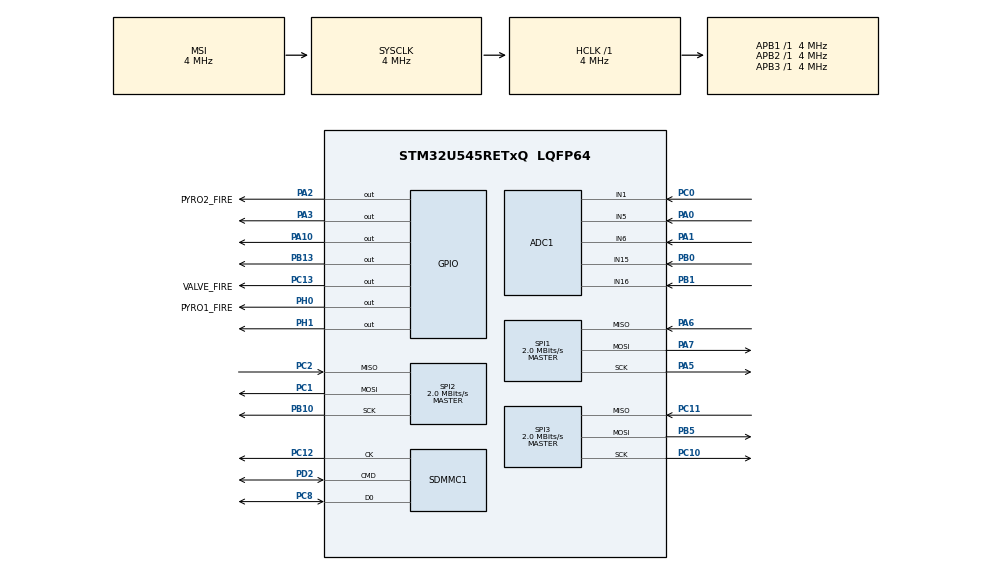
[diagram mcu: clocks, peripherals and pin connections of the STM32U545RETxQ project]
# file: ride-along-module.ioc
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ADC1.Channel-0\#ChannelRegularConversion=ADC_CHANNEL_15
ADC1.MonitoredBy-0\#ChannelRegularConversion=__NULL
ADC1.NbrOfConversionFlag=1
ADC1.OffsetNumber-0\#ChannelRegularConversion=ADC_OFFSET_NONE
ADC1.Rank-0\#ChannelRegularConversion=1
ADC1.SamplingTime-0\#ChannelRegularConversion=ADC_SAMPLETIME_5CYCLE
ADC1.master=1
CORTEX_M33_NS.userName=CORTEX_M33
Mcu.Family=STM32U5
Mcu.Name=STM32U545RETxQ
Mcu.Package=LQFP64
NVIC.PriorityGroup=NVIC_PRIORITYGROUP_4
NVIC.TIM16_IRQn=true\:0\:0\:false\:false\:true\:true\:true\:true
PA0.Mode=IN5-Single-Ended
PA0.Signal=ADC1_IN5
PA1.Mode=IN6-Single-Ended
PA1.Signal=ADC1_IN6
PA10.Signal=GPIO_Output
PA2.GPIO_Label=PYRO2_FIRE
PA2.Signal=GPIO_Output
PA3.Signal=GPIO_Output
PA5.Mode=Full_Duplex_Master
PA5.Signal=SPI1_SCK
PA6.Mode=Full_Duplex_Master
PA6.Signal=SPI1_MISO
PA7.Mode=Full_Duplex_Master
PA7.Signal=SPI1_MOSI
PB0.Mode=IN15-Single-Ended
PB0.Signal=ADC1_IN15
PB1.Mode=IN16-Single-Ended
PB1.Signal=ADC1_IN16
PB10.Mode=Full_Duplex_Master
PB10.Signal=SPI2_SCK
PB13.Signal=GPIO_Output
PB5.Mode=Full_Duplex_Master
PB5.Signal=SPI3_MOSI
PC0.Mode=IN1-Single-Ended
PC0.Signal=ADC1_IN1
PC1.Mode=Full_Duplex_Master
PC1.Signal=SPI2_MOSI
PC10.Mode=Full_Duplex_Master
PC10.Signal=SPI3_SCK
PC11.Mode=Full_Duplex_Master
PC11.Signal=SPI3_MISO
PC12.Mode=SD_1_bit
PC12.Signal=SDMMC1_CK
PC13.GPIO_Label=VALVE_FIRE
PC13.Signal=GPIO_Output
PC2.Mode=Full_Duplex_Master
PC2.Signal=SPI2_MISO
PC8.GPIO_PuPd=GPIO_PULLUP
PC8.Mode=SD_1_bit
PC8.Signal=SDMMC1_D0
PD2.GPIO_PuPd=GPIO_PULLUP
PD2.Mode=SD_1_bit
PD2.Signal=SDMMC1_CMD
PH0-OSC_IN\ (PH0).GPIO_Label=PYRO1_FIRE
PH0-OSC_IN\ (PH0).Signal=GPIO_Output
PH1-OSC_OUT\ (PH1).Signal=GPIO_Output
ProjectManager.HeapSize=0x200
ProjectManager.StackSize=0x400
ProjectManager.TargetToolchain=STM32CubeIDE
RCC.ADCFreq_Value=16000000
RCC.AHBFreq_Value=4000000
RCC.APB1Freq_Value=4000000
RCC.APB1TimFreq_Value=4000000
RCC.APB2Freq_Value=4000000
RCC.APB2TimFreq_Value=4000000
RCC.APB3Freq_Value=4000000
RCC.CortexFreq_Value=4000000
RCC.DACCLockSelectionVirtual=RCC_DAC1CLKSOURCE_LSI
RCC.DACCLockSelectionVirtualString=RCC_DAC1CLKSOURCE_LSI
RCC.EPOD_VALUE=4000000
RCC.HCLKFreq_Value=4000000
RCC.HSE_VALUE=16000000
RCC.HSI48_VALUE=48000000
RCC.HSI_VALUE=16000000
RCC.LSE_VALUE=32768
RCC.LSIDIV_VALUE=32000
RCC.MSI_VALUE=4000000
RCC.PLLFRACN=0
RCC.PWR_Regulator_Voltage_Scale=PWR_REGULATOR_VOLTAGE_SCALE2
RCC.SDMMCClockSelection=RCC_SDMMCCLKSOURCE_CLK48
RCC.SYSCLKFreq_VALUE=4000000
RCC.USBFreq_Value=48000000
RCC.VCOOutputFreq_Value=516000000
SDMMC1.ClockDiv=59
SDMMC1.HardwareFlowControl=SDMMC_HARDWARE_FLOW_CONTROL_DISABLE
SPI1.CalculateBaudRate=2.0 MBits/s
SPI1.DataSize=SPI_DATASIZE_8BIT
SPI1.Direction=SPI_DIRECTION_2LINES
SPI1.Mode=SPI_MODE_MASTER
SPI1.VirtualType=VM_MASTER
SPI2.CalculateBaudRate=2.0 MBits/s
SPI2.DataSize=SPI_DATASIZE_8BIT
SPI2.Direction=SPI_DIRECTION_2LINES
SPI2.Mode=SPI_MODE_MASTER
SPI2.VirtualType=VM_MASTER
SPI3.CalculateBaudRate=2.0 MBits/s
SPI3.DataSize=SPI_DATASIZE_8BIT
SPI3.Direction=SPI_DIRECTION_2LINES
SPI3.Mode=SPI_MODE_MASTER
SPI3.VirtualType=VM_MASTER
TIM16.PeriodNoDither=ms5607MeasurementDelay
TIM16.Prescaler=40-1
VP_LPBAMQUEUE_VS_QUEUE.Mode=QUEUEMODE
VP_MEMORYMAP_VS_MEMORYMAP.Mode=CurAppReg
VP_PWR_VS_SECSignals.Mode=Security/Privilege
VP_PWR_Vdda.Mode=isolationVdda
VP_TIM16_VS_ClockSourceINT.Mode=Enable_Timer
board=custom

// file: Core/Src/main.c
/* USER CODE BEGIN Header */
/**
  ******************************************************************************
  * @file           : main.c
  * @brief          : Main program body
  ******************************************************************************
  * @attention
  *
  * Copyright (c) 2025 STMicroelectronics.
  * All rights reserved.
  *
  * This software is licensed under terms that can be found in the LICENSE file
  * in the root directory of this software component.
  * If no LICENSE file comes with this software, it is provided AS-IS.
  *
  ******************************************************************************
  */
/* USER CODE END Header */
#include "main.h"

ADC_HandleTypeDef hadc1;

SD_HandleTypeDef hsd1;

SPI_HandleTypeDef hspi1;
SPI_HandleTypeDef hspi2;
SPI_HandleTypeDef hspi3;

TIM_HandleTypeDef htim16;

/* USER CODE BEGIN PV */

uint32_t pressure;

MS5607_MeasureState state_check;

/* USER CODE END PV */

void SystemClock_Config(void);
static void MX_GPIO_Init(void);
static void MX_TIM16_Init(void);
static void MX_SPI1_Init(void);
static void MX_SPI2_Init(void);
static void MX_SPI3_Init(void);
static void MX_SDMMC1_SD_Init(void);
static void MX_ADC1_Init(void);
//static void fetch_GPS(void);

/* USER CODE BEGIN 0 */

typedef enum {IDLE, PAD, ASCENT, EMATCH, DESCENT, LANDED} rocketState;

rocketState stateTrack = IDLE;

/* USER CODE END 0 */

int main(void)
{

  /* USER CODE BEGIN 1 */

	char dataMessage[50];
	uint8_t dataMessageLen;

  /* USER CODE END 1 */

  /* MCU Configuration--------------------------------------------------------*/

  /* Reset of all peripherals, Initializes the Flash interface and the Systick. */
  HAL_Init();

  /* USER CODE BEGIN Init */
  __HAL_RCC_PWR_CLK_ENABLE();

  	// Configure MS5607
	MS5607_HandleTypeDef ms5607Config = {0};
  	ms5607Config.spi = &hspi1;
  	ms5607Config.timer = &htim16;
  	ms5607Config.csPort = GPIOA;
  	ms5607Config.csPin = GPIO_PIN_3;
  	ms5607Config.osr = MS5607_OSR_1024;
	MS5607_config(&ms5607Config);

	//Configure LSMDSR
	LSM6DSL_HandleTypeDef lsm6dslConfig = {0};
	lsm6dslConfig.spi = &hspi2;
	lsm6dslConfig.csPort = GPIOH;
	lsm6dslConfig.csPin = GPIO_PIN_1;
	lsm6dslConfig.outputDataRate = LSM6DSL_ODR_104_HZ;
	lsm6dslConfig.accelFullScale = LSM6DSL_ACCEL_FS_PM_16;
	lsm6dslConfig.gyroFullScale = LSM6DSL_GYRO_FS_PM_2000;
	LSM6DSL_config(&lsm6dslConfig);

	//Configure Radio
	radio_HandleTypeDef radioConfig = {};
	radioConfig.spi = &hspi3;
	radioConfig.csPort = GPIOB;
	radioConfig.csPin = GPIO_PIN_4;
	radio_config(&radioConfig);

  /* USER CODE END Init */

  /* Configure the system clock */
  SystemClock_Config();

  /* Initialize all configured peripherals */
  MX_GPIO_Init();
  MX_TIM16_Init();
  MX_SPI1_Init();
  MX_SPI2_Init();
  MX_SPI3_Init();
  MX_SDMMC1_SD_Init();
  MX_ADC1_Init();
  /* USER CODE BEGIN 2 */

//  MS5607_init();
	//LSM6DSL_init();

	//MS5607_readUncompPres();

	int16_t accel[3];
	int16_t gyro[3];
//
// Test MicroSD card write
  	//Linking SD Card
	MX_FATFS_Init();
//
	FRESULT res;
	FATFS fs;
//
	res = f_mount(&fs, "", 1);
	if (res != FR_OK)
	{
		Error_Handler();
	}
//	res = log_init();
//
//	res = log_status("INFO", "Mounted successfully.");
//	if (res != FR_OK)
//	{
//		Error_Handler();
//	}
////
//	res = log_status("INFO", "Beginning MS506777 INIT");
//	if (res != FR_OK)
//		{
//			Error_Handler();
//		}
	MS5607_init();

//	log_status("INFO", "Beginning LSM6DSL INIT");
	LSM6DSL_init();

	radio_init();
//
//	uint8_t whoami = LSM6DSL_readRegister(LSM6DSL_CTRL2_G);
//
	FIL csv;
	res = f_open_append(&csv, "flight0.csv");
	if (res != FR_OK)
	{
		Error_Handler();
	}

	f_printf(&csv, "Tick, rawPressure, Pressure, AccelX, AccelY, AccelZ, GyroX, GyroY, GyroZ\n");
	res = f_sync(&csv);
	if (res != FR_OK)
	{
		Error_Handler();
	}
//
//	MS5607_readUncompPres();

  /* USER CODE END 2 */

  /* Infinite loop */
  /* USER CODE BEGIN WHILE */
//	GPIO_PinState pinmode;

	uint16_t raw;
	uint32_t camera_cntr = 0;

  while (1)
  {

//typedef enum {IDLE, PAD, ASCENT, EMATCH, DESCENT} rocketState;
//
//	switch (stateTrack) {
//		case IDLE: //default state, set at stateTrack variable definition
//			if (rocket_Idle() == 1) stateTrack = PAD; //In IDLE state only the main MCU is powered.
//			break;					//Transitions to PAD state when radio module is powered at the same time (and rocket accelerometer is pointed up?
//		case PAD:// When rocket is sensed as upright and Main + Radio MCUs are powered simultaneously
//			if (rocket_PAD() == 1) stateTrack = ASCENT; //In PAD state, accelerometer data is being monitored and buffered (but not saved to SD)
//			break;					   //when accelerometer data is above [insert number]g for [insert number] samples transition to ascent
//		case ASCENT://Starting when rocket is in powered flight, determines the moment of apogee, also triggers data writing to SD card
//			if(rocket_ASCENT() == 1) stateTrack = DESCENT;
//			break;
//		case DESCENT:
//			if(rocket_DESCENT() == 2){stateTrack = EMATCH;}
//			else if(rocket_descent == 1){stateTrack = LANDED;}
//		case EMATCH:
//			if(rocket_EMATCH() == 1) stateTrack = DESCENT;
//		case LANDED:
//			break;
//		}

	  state_check = MS5607_getState();
	if (state_check == MS5607_IDLE)
	{
//		 Compensate digital reading
		MS5607_CompVal compVals = MS5607_getCompValues();
		MS5607_RawVal rawVals = MS5607_getRawValues();
//		log_status("INFO", "Got altimeter values");
	  	LSM6DSL_updateAccel();
	  	LSM6DSL_updateGyro();
		LSM6DSL_getAccel(accel);
		LSM6DSL_getGyro(gyro);

//		f_printf(&csv, "%d, %d, %d\n", HAL_GetTick(), rawVals.pres, compVals.pres);
		f_printf(&csv, "%d, %d, %d, %d, %d, %d, %d, %d, %d\n", HAL_GetTick(), rawVals.pres, compVals.pres, accel[0], accel[1], accel[2], gyro[0], gyro[1], gyro[2]);
		f_sync(&csv);
		HAL_Delay(5);

		// Measure again
		MS5607_readUncompPres();
	}
//////////////////////////////////////////////////////////////////

    /* USER CODE END WHILE */

  }
}

void SystemClock_Config(void)
{
  RCC_OscInitTypeDef RCC_OscInitStruct = {0};
  RCC_ClkInitTypeDef RCC_ClkInitStruct = {0};

  /** Configure the main internal regulator output voltage
  */
  if (HAL_PWREx_ControlVoltageScaling(PWR_REGULATOR_VOLTAGE_SCALE2) != HAL_OK)
  {
    Error_Handler();
  }

  /** Initializes the CPU, AHB and APB buses clocks
  */
  RCC_OscInitStruct.OscillatorType = RCC_OSCILLATORTYPE_HSI48|RCC_OSCILLATORTYPE_HSI
                              |RCC_OSCILLATORTYPE_MSI;
  RCC_OscInitStruct.HSIState = RCC_HSI_ON;
  RCC_OscInitStruct.HSI48State = RCC_HSI48_ON;
  RCC_OscInitStruct.HSICalibrationValue = RCC_HSICALIBRATION_DEFAULT;
  RCC_OscInitStruct.MSIState = RCC_MSI_ON;
  RCC_OscInitStruct.MSICalibrationValue = RCC_MSICALIBRATION_DEFAULT;
  RCC_OscInitStruct.MSIClockRange = RCC_MSIRANGE_4;
  RCC_OscInitStruct.PLL.PLLState = RCC_PLL_NONE;
  if (HAL_RCC_OscConfig(&RCC_OscInitStruct) != HAL_OK)
  {
    Error_Handler();
  }

  /** Initializes the CPU, AHB and APB buses clocks
  */
  RCC_ClkInitStruct.ClockType = RCC_CLOCKTYPE_HCLK|RCC_CLOCKTYPE_SYSCLK
                              |RCC_CLOCKTYPE_PCLK1|RCC_CLOCKTYPE_PCLK2
                              |RCC_CLOCKTYPE_PCLK3;
  RCC_ClkInitStruct.SYSCLKSource = RCC_SYSCLKSOURCE_MSI;
  RCC_ClkInitStruct.AHBCLKDivider = RCC_SYSCLK_DIV1;
  RCC_ClkInitStruct.APB1CLKDivider = RCC_HCLK_DIV1;
  RCC_ClkInitStruct.APB2CLKDivider = RCC_HCLK_DIV1;
  RCC_ClkInitStruct.APB3CLKDivider = RCC_HCLK_DIV1;

  if (HAL_RCC_ClockConfig(&RCC_ClkInitStruct, FLASH_LATENCY_0) != HAL_OK)
  {
    Error_Handler();
  }
}

static void MX_ADC1_Init(void)
{

  ADC_ChannelConfTypeDef sConfig = {0};

  /** Common config
  */
  hadc1.Instance = ADC1;
  hadc1.Init.ClockPrescaler = ADC_CLOCK_ASYNC_DIV1;
  hadc1.Init.Resolution = ADC_RESOLUTION_14B;
  hadc1.Init.GainCompensation = 0;
  hadc1.Init.DataAlign = ADC_DATAALIGN_RIGHT;
  hadc1.Init.ScanConvMode = ADC_SCAN_DISABLE;
  hadc1.Init.EOCSelection = ADC_EOC_SINGLE_CONV;
  hadc1.Init.LowPowerAutoWait = DISABLE;
  hadc1.Init.ContinuousConvMode = DISABLE;
  hadc1.Init.NbrOfConversion = 1;
  hadc1.Init.DiscontinuousConvMode = DISABLE;
  hadc1.Init.ExternalTrigConv = ADC_SOFTWARE_START;
  hadc1.Init.ExternalTrigConvEdge = ADC_EXTERNALTRIGCONVEDGE_NONE;
  hadc1.Init.DMAContinuousRequests = DISABLE;
  hadc1.Init.TriggerFrequencyMode = ADC_TRIGGER_FREQ_HIGH;
  hadc1.Init.Overrun = ADC_OVR_DATA_PRESERVED;
  hadc1.Init.LeftBitShift = ADC_LEFTBITSHIFT_NONE;
  hadc1.Init.ConversionDataManagement = ADC_CONVERSIONDATA_DR;
  hadc1.Init.OversamplingMode = DISABLE;
  if (HAL_ADC_Init(&hadc1) != HAL_OK)
  {
    Error_Handler();
  }

  /** Configure Regular Channel
  */
  sConfig.Channel = ADC_CHANNEL_15;
  sConfig.Rank = ADC_REGULAR_RANK_1;
  sConfig.SamplingTime = ADC_SAMPLETIME_5CYCLE;
  sConfig.SingleDiff = ADC_SINGLE_ENDED;
  sConfig.OffsetNumber = ADC_OFFSET_NONE;
  sConfig.Offset = 0;
  if (HAL_ADC_ConfigChannel(&hadc1, &sConfig) != HAL_OK)
  {
    Error_Handler();
  }

}

static void MX_SDMMC1_SD_Init(void)
{

  hsd1.Instance = SDMMC1;
  hsd1.Init.ClockEdge = SDMMC_CLOCK_EDGE_RISING;
  hsd1.Init.ClockPowerSave = SDMMC_CLOCK_POWER_SAVE_DISABLE;
  hsd1.Init.BusWide = SDMMC_BUS_WIDE_1B;
  hsd1.Init.HardwareFlowControl = SDMMC_HARDWARE_FLOW_CONTROL_DISABLE;
  hsd1.Init.ClockDiv = 59;
  if (HAL_SD_Init(&hsd1) != HAL_OK)
  {
    Error_Handler();
  }

}

static void MX_SPI1_Init(void)
{

  SPI_AutonomousModeConfTypeDef HAL_SPI_AutonomousMode_Cfg_Struct = {0};

  /* SPI1 parameter configuration*/
  hspi1.Instance = SPI1;
  hspi1.Init.Mode = SPI_MODE_MASTER;
  hspi1.Init.Direction = SPI_DIRECTION_2LINES;
  hspi1.Init.DataSize = SPI_DATASIZE_8BIT;
  hspi1.Init.CLKPolarity = SPI_POLARITY_LOW;
  hspi1.Init.CLKPhase = SPI_PHASE_1EDGE;
  hspi1.Init.NSS = SPI_NSS_SOFT;
  hspi1.Init.BaudRatePrescaler = SPI_BAUDRATEPRESCALER_2;
  hspi1.Init.FirstBit = SPI_FIRSTBIT_MSB;
  hspi1.Init.TIMode = SPI_TIMODE_DISABLE;
  hspi1.Init.CRCCalculation = SPI_CRCCALCULATION_DISABLE;
  hspi1.Init.CRCPolynomial = 0x7;
  hspi1.Init.NSSPMode = SPI_NSS_PULSE_ENABLE;
  hspi1.Init.NSSPolarity = SPI_NSS_POLARITY_LOW;
  hspi1.Init.FifoThreshold = SPI_FIFO_THRESHOLD_01DATA;
  hspi1.Init.MasterSSIdleness = SPI_MASTER_SS_IDLENESS_00CYCLE;
  hspi1.Init.MasterInterDataIdleness = SPI_MASTER_INTERDATA_IDLENESS_00CYCLE;
  hspi1.Init.MasterReceiverAutoSusp = SPI_MASTER_RX_AUTOSUSP_DISABLE;
  hspi1.Init.MasterKeepIOState = SPI_MASTER_KEEP_IO_STATE_DISABLE;
  hspi1.Init.IOSwap = SPI_IO_SWAP_DISABLE;
  hspi1.Init.ReadyMasterManagement = SPI_RDY_MASTER_MANAGEMENT_INTERNALLY;
  hspi1.Init.ReadyPolarity = SPI_RDY_POLARITY_HIGH;
  if (HAL_SPI_Init(&hspi1) != HAL_OK)
  {
    Error_Handler();
  }
  HAL_SPI_AutonomousMode_Cfg_Struct.TriggerState = SPI_AUTO_MODE_DISABLE;
  HAL_SPI_AutonomousMode_Cfg_Struct.TriggerSelection = SPI_GRP1_GPDMA_CH0_TCF_TRG;
  HAL_SPI_AutonomousMode_Cfg_Struct.TriggerPolarity = SPI_TRIG_POLARITY_RISING;
  if (HAL_SPIEx_SetConfigAutonomousMode(&hspi1, &HAL_SPI_AutonomousMode_Cfg_Struct) != HAL_OK)
  {
    Error_Handler();
  }

}

static void MX_SPI2_Init(void)
{

  SPI_AutonomousModeConfTypeDef HAL_SPI_AutonomousMode_Cfg_Struct = {0};

  /* SPI2 parameter configuration*/
  hspi2.Instance = SPI2;
  hspi2.Init.Mode = SPI_MODE_MASTER;
  hspi2.Init.Direction = SPI_DIRECTION_2LINES;
  hspi2.Init.DataSize = SPI_DATASIZE_16BIT;
  hspi2.Init.CLKPolarity = SPI_POLARITY_LOW;
  hspi2.Init.CLKPhase = SPI_PHASE_1EDGE;
  hspi2.Init.NSS = SPI_NSS_SOFT;
  hspi2.Init.BaudRatePrescaler = SPI_BAUDRATEPRESCALER_2;
  hspi2.Init.FirstBit = SPI_FIRSTBIT_MSB;
  hspi2.Init.TIMode = SPI_TIMODE_DISABLE;
  hspi2.Init.CRCCalculation = SPI_CRCCALCULATION_DISABLE;
  hspi2.Init.CRCPolynomial = 0x7;
  hspi2.Init.NSSPMode = SPI_NSS_PULSE_ENABLE;
  hspi2.Init.NSSPolarity = SPI_NSS_POLARITY_LOW;
  hspi2.Init.FifoThreshold = SPI_FIFO_THRESHOLD_01DATA;
  hspi2.Init.MasterSSIdleness = SPI_MASTER_SS_IDLENESS_00CYCLE;
  hspi2.Init.MasterInterDataIdleness = SPI_MASTER_INTERDATA_IDLENESS_00CYCLE;
  hspi2.Init.MasterReceiverAutoSusp = SPI_MASTER_RX_AUTOSUSP_DISABLE;
  hspi2.Init.MasterKeepIOState = SPI_MASTER_KEEP_IO_STATE_DISABLE;
  hspi2.Init.IOSwap = SPI_IO_SWAP_DISABLE;
  hspi2.Init.ReadyMasterManagement = SPI_RDY_MASTER_MANAGEMENT_INTERNALLY;
  hspi2.Init.ReadyPolarity = SPI_RDY_POLARITY_HIGH;
  if (HAL_SPI_Init(&hspi2) != HAL_OK)
  {
    Error_Handler();
  }
  HAL_SPI_AutonomousMode_Cfg_Struct.TriggerState = SPI_AUTO_MODE_DISABLE;
  HAL_SPI_AutonomousMode_Cfg_Struct.TriggerSelection = SPI_GRP1_GPDMA_CH0_TCF_TRG;
  HAL_SPI_AutonomousMode_Cfg_Struct.TriggerPolarity = SPI_TRIG_POLARITY_RISING;
  if (HAL_SPIEx_SetConfigAutonomousMode(&hspi2, &HAL_SPI_AutonomousMode_Cfg_Struct) != HAL_OK)
  {
    Error_Handler();
  }

}

static void MX_SPI3_Init(void)
{

  SPI_AutonomousModeConfTypeDef HAL_SPI_AutonomousMode_Cfg_Struct = {0};

  /* SPI3 parameter configuration*/
  hspi3.Instance = SPI3;
  hspi3.Init.Mode = SPI_MODE_MASTER;
  hspi3.Init.Direction = SPI_DIRECTION_2LINES;
  hspi3.Init.DataSize = SPI_DATASIZE_8BIT;
  hspi3.Init.CLKPolarity = SPI_POLARITY_LOW;
  hspi3.Init.CLKPhase = SPI_PHASE_1EDGE;
  hspi3.Init.NSS = SPI_NSS_SOFT;
  hspi3.Init.BaudRatePrescaler = SPI_BAUDRATEPRESCALER_2;
  hspi3.Init.FirstBit = SPI_FIRSTBIT_MSB;
  hspi3.Init.TIMode = SPI_TIMODE_DISABLE;
  hspi3.Init.CRCCalculation = SPI_CRCCALCULATION_DISABLE;
  hspi3.Init.CRCPolynomial = 0x7;
  hspi3.Init.NSSPMode = SPI_NSS_PULSE_ENABLE;
  hspi3.Init.NSSPolarity = SPI_NSS_POLARITY_LOW;
  hspi3.Init.FifoThreshold = SPI_FIFO_THRESHOLD_01DATA;
  hspi3.Init.MasterSSIdleness = SPI_MASTER_SS_IDLENESS_00CYCLE;
  hspi3.Init.MasterInterDataIdleness = SPI_MASTER_INTERDATA_IDLENESS_00CYCLE;
  hspi3.Init.MasterReceiverAutoSusp = SPI_MASTER_RX_AUTOSUSP_DISABLE;
  hspi3.Init.MasterKeepIOState = SPI_MASTER_KEEP_IO_STATE_DISABLE;
  hspi3.Init.IOSwap = SPI_IO_SWAP_DISABLE;
  hspi3.Init.ReadyMasterManagement = SPI_RDY_MASTER_MANAGEMENT_INTERNALLY;
  hspi3.Init.ReadyPolarity = SPI_RDY_POLARITY_HIGH;
  if (HAL_SPI_Init(&hspi3) != HAL_OK)
  {
    Error_Handler();
  }
  HAL_SPI_AutonomousMode_Cfg_Struct.TriggerState = SPI_AUTO_MODE_DISABLE;
  HAL_SPI_AutonomousMode_Cfg_Struct.TriggerSelection = SPI_GRP2_LPDMA_CH0_TCF_TRG;
  HAL_SPI_AutonomousMode_Cfg_Struct.TriggerPolarity = SPI_TRIG_POLARITY_RISING;
  if (HAL_SPIEx_SetConfigAutonomousMode(&hspi3, &HAL_SPI_AutonomousMode_Cfg_Struct) != HAL_OK)
  {
    Error_Handler();
  }

}

static void MX_TIM16_Init(void)
{

  /* USER CODE BEGIN TIM16_Init 0 */
	uint16_t ms5607MeasurementDelay = MS5607_getMeasurementDelay();
  /* USER CODE END TIM16_Init 0 */

  htim16.Instance = TIM16;
  htim16.Init.Prescaler = 40-1;
  htim16.Init.CounterMode = TIM_COUNTERMODE_UP;
  htim16.Init.Period = ms5607MeasurementDelay;
  htim16.Init.ClockDivision = TIM_CLOCKDIVISION_DIV1;
  htim16.Init.RepetitionCounter = 0;
  htim16.Init.AutoReloadPreload = TIM_AUTORELOAD_PRELOAD_DISABLE;
  if (HAL_TIM_Base_Init(&htim16) != HAL_OK)
  {
    Error_Handler();
  }

}

static void MX_GPIO_Init(void)
{
  GPIO_InitTypeDef GPIO_InitStruct = {0};

  /* GPIO Ports Clock Enable */
  __HAL_RCC_GPIOC_CLK_ENABLE();
  __HAL_RCC_GPIOH_CLK_ENABLE();
  __HAL_RCC_GPIOA_CLK_ENABLE();
  __HAL_RCC_GPIOB_CLK_ENABLE();
  __HAL_RCC_GPIOD_CLK_ENABLE();

  /*Configure GPIO pin Output Level */
  HAL_GPIO_WritePin(VALVE_FIRE_GPIO_Port, VALVE_FIRE_Pin, GPIO_PIN_RESET);

  /*Configure GPIO pin Output Level */
  HAL_GPIO_WritePin(GPIOH, PYRO1_FIRE_Pin|GPIO_PIN_1, GPIO_PIN_RESET);

  /*Configure GPIO pin Output Level */
  HAL_GPIO_WritePin(GPIOA, PYRO2_FIRE_Pin|GPIO_PIN_3, GPIO_PIN_RESET);

  /*Configure GPIO pin Output Level */
  HAL_GPIO_WritePin(GPIOB, GPIO_PIN_4, GPIO_PIN_RESET);
  HAL_GPIO_WritePin(GPIOB, CAMERA_Toggle_Pin, GPIO_PIN_RESET); //camera toggle pin

  /*Configure GPIO pin : VALVE_FIRE_Pin */
  GPIO_InitStruct.Pin = VALVE_FIRE_Pin;
  GPIO_InitStruct.Mode = GPIO_MODE_OUTPUT_PP;
  GPIO_InitStruct.Pull = GPIO_NOPULL;
  GPIO_InitStruct.Speed = GPIO_SPEED_FREQ_LOW;
  HAL_GPIO_Init(VALVE_FIRE_GPIO_Port, &GPIO_InitStruct);

  /*Configure GPIO pins : PYRO1_FIRE_Pin PH1 and IMU_CS *//////////////////
  GPIO_InitStruct.Pin = PYRO1_FIRE_Pin|GPIO_PIN_1;
  GPIO_InitStruct.Mode = GPIO_MODE_OUTPUT_PP;
  GPIO_InitStruct.Pull = GPIO_NOPULL;
  GPIO_InitStruct.Speed = GPIO_SPEED_FREQ_LOW;
  HAL_GPIO_Init(GPIOH, &GPIO_InitStruct);

  /*Configure GPIO pins : IMU_INT1_Pin IMU_INT2_Pin *//////////////////////////
  GPIO_InitStruct.Pin = IMU_INT1_Pin|IMU_INT2_Pin;
  GPIO_InitStruct.Mode = GPIO_MODE_IT_RISING;
  GPIO_InitStruct.Pull = GPIO_NOPULL;
  HAL_GPIO_Init(GPIOC, &GPIO_InitStruct);

  /*Configure GPIO pins : PYRO2_FIRE_Pin PA2 and PRES_CS*/
  GPIO_InitStruct.Pin = PYRO2_FIRE_Pin|GPIO_PIN_3;
  GPIO_InitStruct.Mode = GPIO_MODE_OUTPUT_PP;
  GPIO_InitStruct.Pull = GPIO_NOPULL;
  GPIO_InitStruct.Speed = GPIO_SPEED_FREQ_LOW;
  HAL_GPIO_Init(GPIOA, &GPIO_InitStruct);

  /*Configure GPIO pins : PYRO1_ADC_Pin PA0 *///////////////////////////////////
  GPIO_InitStruct.Pin = PYRO1_ADC_Pin;
  GPIO_InitStruct.Mode = GPIO_MODE_IT_RISING;
  GPIO_InitStruct.Pull = GPIO_NOPULL;
  HAL_GPIO_Init(PYRO1_ADC_Port, &GPIO_InitStruct);
  /*Configure GPIO pins : PYRO2_ADC_Pin PA1 *///////////////////////////////////
  GPIO_InitStruct.Pin = PYRO2_ADC_Pin;
  GPIO_InitStruct.Mode = GPIO_MODE_IT_RISING;
  GPIO_InitStruct.Pull = GPIO_NOPULL;
  HAL_GPIO_Init(PYRO2_ADC_Port, &GPIO_InitStruct);

  GPIO_InitStruct.Pin = GPIO_PIN_4|GPIO_PIN_13;
  GPIO_InitStruct.Mode = GPIO_MODE_OUTPUT_PP;
  GPIO_InitStruct.Pull = GPIO_NOPULL;
  HAL_GPIO_Init(GPIOB, &GPIO_InitStruct);

}

/* USER CODE BEGIN 4 */

void HAL_TIM_PeriodElapsedCallback(TIM_HandleTypeDef *htim)
{
	if (htim == &htim16)
	{
		HAL_TIM_Base_Stop_IT(&htim16);
		MS5607_TimerCallback();
		//pressure = readMS5607ADC();
	}
}

void HAL_GPIO_EXTI_Callback(uint16_t gpioPin)
{
	log_status("INFO", "LSM6DSL data ready");
	switch (gpioPin)
	{
		case IMU_INT1_Pin:
			//LSM6DSL_updateAccel();
		case IMU_INT2_Pin:
			//LSM6DSL_updateGyro();
	}
}

/* USER CODE END 4 */

void Error_Handler(void)
{
  __disable_irq();
  while (1)
  {
  }
}

//old junk::

//Write pyro trigger pin high
//Write pyro trigger pin Low
//ADC read continuity
//Decide action based on continuity (Write SD card success or fail, retry if fail)

/////////////////////////Pyro1
//		HAL_Delay(1000); //Pyro01 Fire = PH0, ADCin1 = PA0
//	  	HAL_GPIO_WritePin(PYRO1_FIRE_GPIO_Port, PYRO1_FIRE_Pin, GPIO_PIN_SET);
//	  	log_status("INFO", "PYRO1 Set HIGH");
//		// Get ADC value
////		HAL_ADC_Start(&hadc1);
////		HAL_ADC_PollForConversion(&hadc1, HAL_MAX_DELAY);
////		raw = HAL_ADC_GetValue(&hadc1);
//
//	  	HAL_Delay(1000);
//	  	HAL_GPIO_WritePin(PYRO1_FIRE_GPIO_Port, PYRO1_FIRE_Pin, GPIO_PIN_RESET);
//	  	log_status("INFO", "PYRO1 Set LOW");
//
//	  	////////////////////////Pyro 2
//	  	HAL_Delay(1000); //Pyro02 Fire = PA2, ADCin2 = PA1
//		HAL_GPIO_WritePin(PYRO2_FIRE_GPIO_Port, PYRO2_FIRE_Pin, GPIO_PIN_SET);
//		log_status("INFO", "PYRO2 Set HIGH");
//		// Get ADC value
////		HAL_ADC_Start(&hadc1);
////		HAL_ADC_PollForConversion(&hadc1, HAL_MAX_DELAY);
////		raw = HAL_ADC_GetValue(&hadc1);
//		HAL_Delay(1000);
//		HAL_GPIO_WritePin(PYRO2_FIRE_GPIO_Port, PYRO2_FIRE_Pin, GPIO_PIN_RESET);
//		log_status("INFO", "PYRO1 Set LOW");
////
//	  HAL_GPIO_TogglePin(GPIOA, GPIO_PIN_5);
//	  pinmode = HAL_GPIO_ReadPin(GPIOA, GPIO_PIN_5);
//	  if(pinmode == GPIO_PIN_SET){
//		  f_printf(&csv, "%d, LED Pin set:, High\n", HAL_GetTick());
//		  res = f_sync(&csv);
//		  	if (res != FR_OK)
//		  	{
//		  		Error_Handler();
//		  	}
//	  }else{
//		  f_printf(&csv, "%d, LED Pin set:, Low\n", HAL_GetTick());
//		  res = f_sync(&csv);
//		  	if (res != FR_OK)
//		  	{
//		  		Error_Handler();
//		  	}
//	  }

//////////////////////////////////////////////////////////////////
